VERSION 5.7 ;
  NOWIREEXTENSIONATPIN ON ;
  DIVIDERCHAR "/" ;
  BUSBITCHARS "[]" ;
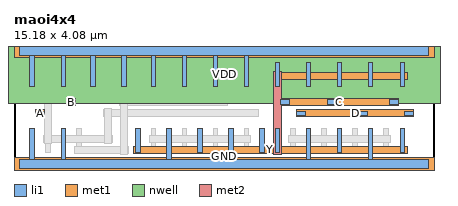
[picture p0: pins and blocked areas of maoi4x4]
MACRO maoi4x4
  CLASS BLOCK ;
  FOREIGN maoi4x4 ;
  ORIGIN 0.000 0.000 ;
  SIZE 15.180 BY 4.080 ;
  PIN A
    ANTENNAGATEAREA 0.596400 ;
    PORT
      LAYER li1 ;
        RECT 0.775 1.745 1.105 1.915 ;
      LAYER met1 ;
        RECT 0.780 1.700 1.100 1.960 ;
    END
  END A
  PIN VDD
    ANTENNADIFFAREA 6.620400 ;
    PORT
      LAYER nwell ;
        RECT -0.230 2.200 15.410 4.410 ;
      LAYER li1 ;
        RECT 0.210 3.915 14.970 4.245 ;
        RECT 0.570 2.800 0.740 3.915 ;
        RECT 1.700 2.800 1.870 3.915 ;
        RECT 2.760 2.800 2.930 3.915 ;
        RECT 3.880 2.800 4.050 3.915 ;
        RECT 4.960 2.800 5.130 3.915 ;
        RECT 6.080 2.800 6.250 3.915 ;
        RECT 7.200 2.800 7.370 3.915 ;
        RECT 8.320 2.800 8.490 3.915 ;
      LAYER met1 ;
        RECT 0.000 3.840 15.180 4.320 ;
    END
  END VDD
  PIN GND
    ANTENNADIFFAREA 5.717400 ;
    PORT
      LAYER li1 ;
        RECT 0.570 0.165 0.740 1.280 ;
        RECT 1.700 0.165 1.870 1.280 ;
        RECT 5.520 0.165 5.690 1.280 ;
        RECT 7.760 0.165 7.930 1.280 ;
        RECT 10.560 0.165 10.730 1.280 ;
        RECT 12.800 0.165 12.970 1.280 ;
        RECT 0.210 -0.165 14.970 0.165 ;
      LAYER met1 ;
        RECT 0.000 -0.240 15.180 0.240 ;
    END
  END GND
  PIN B
    ANTENNAGATEAREA 0.596400 ;
    PORT
      LAYER li1 ;
        RECT 1.905 2.145 2.235 2.315 ;
      LAYER met1 ;
        RECT 1.910 2.100 2.230 2.360 ;
    END
  END B
  PIN Y
    ANTENNADIFFAREA 2.973600 ;
    PORT
      LAYER li1 ;
        RECT 9.440 2.800 9.610 3.680 ;
        RECT 10.560 2.800 10.730 3.680 ;
        RECT 11.680 2.800 11.850 3.680 ;
        RECT 12.800 2.800 12.970 3.680 ;
        RECT 13.960 2.800 14.130 3.680 ;
        RECT 4.400 0.400 4.570 1.280 ;
        RECT 6.640 0.400 6.810 1.280 ;
        RECT 8.880 0.400 9.050 1.280 ;
        RECT 9.440 0.400 9.610 1.280 ;
        RECT 11.680 0.400 11.850 1.280 ;
        RECT 13.960 0.400 14.130 1.280 ;
      LAYER met1 ;
        RECT 9.365 3.040 14.205 3.300 ;
        RECT 4.325 0.380 14.205 0.640 ;
      LAYER met2 ;
        RECT 9.395 0.350 9.655 3.330 ;
    END
  END Y
  PIN D
    ANTENNAGATEAREA 1.780800 ;
    PORT
      LAYER li1 ;
        RECT 10.200 1.745 10.530 1.915 ;
        RECT 12.440 1.745 12.770 1.915 ;
        RECT 14.120 1.745 14.450 1.915 ;
      LAYER met1 ;
        RECT 10.205 1.700 14.445 1.960 ;
    END
  END D
  PIN C
    ANTENNAGATEAREA 1.780800 ;
    PORT
      LAYER li1 ;
        RECT 9.640 2.145 9.970 2.315 ;
        RECT 11.320 2.145 11.650 2.315 ;
        RECT 13.560 2.145 13.890 2.315 ;
      LAYER met1 ;
        RECT 9.645 2.100 13.885 2.360 ;
    END
  END C
  OBS
      LAYER li1 ;
        RECT 1.140 2.800 1.310 3.680 ;
        RECT 2.270 2.800 2.440 3.680 ;
        RECT 3.320 2.800 3.490 3.680 ;
        RECT 4.400 2.800 4.570 3.680 ;
        RECT 5.520 2.800 5.690 3.680 ;
        RECT 6.640 2.800 6.810 3.680 ;
        RECT 7.760 2.800 7.930 3.680 ;
        RECT 8.880 2.800 9.050 3.680 ;
        RECT 10.000 2.800 10.170 3.680 ;
        RECT 11.120 2.800 11.290 3.680 ;
        RECT 12.240 2.800 12.410 3.680 ;
        RECT 13.360 2.800 13.530 3.680 ;
        RECT 14.440 2.800 14.610 3.680 ;
        RECT 4.040 2.145 4.370 2.315 ;
        RECT 5.160 2.145 5.490 2.315 ;
        RECT 7.400 2.145 7.730 2.315 ;
        RECT 3.480 1.745 3.810 1.915 ;
        RECT 4.600 1.745 4.930 1.915 ;
        RECT 6.280 1.745 6.610 1.915 ;
        RECT 8.520 1.745 8.850 1.915 ;
        RECT 1.140 0.400 1.310 1.280 ;
        RECT 2.270 0.400 2.440 1.280 ;
        RECT 4.960 0.400 5.130 1.280 ;
        RECT 6.080 0.400 6.250 1.280 ;
        RECT 7.200 0.400 7.370 1.280 ;
        RECT 8.320 0.400 8.490 1.280 ;
        RECT 10.000 0.400 10.170 1.280 ;
        RECT 11.120 0.400 11.290 1.280 ;
        RECT 12.240 0.400 12.410 1.280 ;
        RECT 13.360 0.400 13.530 1.280 ;
      LAYER met1 ;
        RECT 2.195 3.440 4.125 3.700 ;
        RECT 8.805 3.440 14.685 3.700 ;
        RECT 1.065 3.040 1.385 3.300 ;
        RECT 3.245 3.040 9.125 3.300 ;
        RECT 3.805 2.100 7.725 2.360 ;
        RECT 3.245 1.700 8.845 1.960 ;
        RECT 1.065 0.780 3.565 1.040 ;
        RECT 4.885 0.780 8.565 1.040 ;
        RECT 9.925 0.780 13.605 1.040 ;
        RECT 2.195 0.380 4.125 0.640 ;
      LAYER met2 ;
        RECT 1.095 0.750 1.355 3.330 ;
        RECT 3.275 0.750 3.535 1.990 ;
        RECT 3.835 0.350 4.095 3.730 ;
        RECT 8.835 3.010 9.095 3.730 ;
  END
END maoi4x4
END LIBRARY

